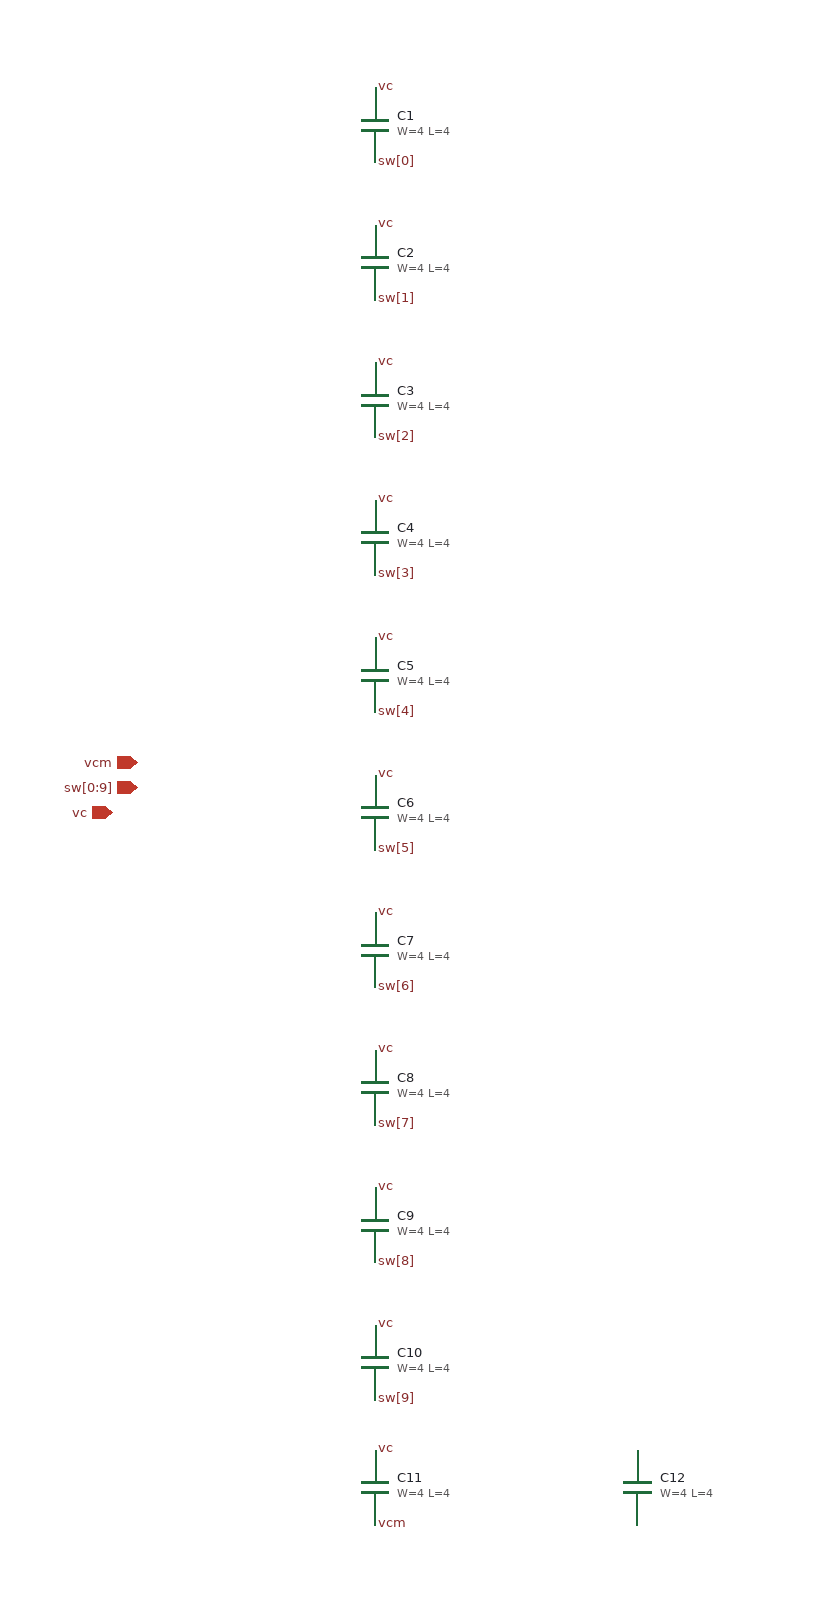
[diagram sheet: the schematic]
v {xschem version=3.4.6 file_version=1.2}
G {}
K {}
V {}
S {}
E {}
C {devices/lab_wire.sym} 420 -90 2 0 {name=p1 sig_type=std_logic lab=vcm}
C {devices/lab_wire.sym} 420 -190 2 0 {name=p3 sig_type=std_logic lab=sw[9]}
C {devices/lab_wire.sym} 420 -300 2 0 {name=p5 sig_type=std_logic lab=sw[8]}
C {devices/lab_wire.sym} 420 -410 2 0 {name=p7 sig_type=std_logic lab=sw[7]}
C {devices/lab_wire.sym} 420 -520 2 0 {name=p9 sig_type=std_logic lab=sw[6]}
C {devices/lab_wire.sym} 420 -630 2 0 {name=p11 sig_type=std_logic lab=sw[5]}
C {devices/lab_wire.sym} 420 -740 2 0 {name=p13 sig_type=std_logic lab=sw[4]}
C {devices/lab_wire.sym} 420 -850 2 0 {name=p15 sig_type=std_logic lab=sw[3]}
C {devices/lab_wire.sym} 420 -960 2 0 {name=p17 sig_type=std_logic lab=sw[2]}
C {devices/ipin.sym} 230 -680 0 0 {name=p53 lab=sw[0:9]}
C {devices/ipin.sym} 230 -700 0 0 {name=p54 lab=vcm}
C {devices/iopin.sym} 210 -660 0 0 {name=p56 lab=vc

}
C {devices/lab_wire.sym} 420 -1020 0 1 {name=p32 sig_type=std_logic lab=vc}
C {sky130_fd_pr/cap_mim_m3_1.sym} 420 -990 0 0 {name=C3 model=cap_mim_m3_1 W=4 L=4 MF=128 spiceprefix=X}
C {devices/lab_wire.sym} 420 -910 0 1 {name=p33 sig_type=std_logic lab=vc}
C {sky130_fd_pr/cap_mim_m3_1.sym} 420 -880 0 0 {name=C4 model=cap_mim_m3_1 W=4 L=4 MF=64 spiceprefix=X}
C {devices/lab_wire.sym} 420 -800 0 1 {name=p34 sig_type=std_logic lab=vc}
C {sky130_fd_pr/cap_mim_m3_1.sym} 420 -770 0 0 {name=C5 model=cap_mim_m3_1 W=4 L=4 MF=32 spiceprefix=X}
C {devices/lab_wire.sym} 420 -690 0 1 {name=p35 sig_type=std_logic lab=vc}
C {sky130_fd_pr/cap_mim_m3_1.sym} 420 -660 0 0 {name=C6 model=cap_mim_m3_1 W=4 L=4 MF=16 spiceprefix=X}
C {devices/lab_wire.sym} 420 -580 0 1 {name=p36 sig_type=std_logic lab=vc}
C {sky130_fd_pr/cap_mim_m3_1.sym} 420 -550 0 0 {name=C7 model=cap_mim_m3_1 W=4 L=4 MF=8 spiceprefix=X}
C {devices/lab_wire.sym} 420 -470 0 1 {name=p37 sig_type=std_logic lab=vc}
C {sky130_fd_pr/cap_mim_m3_1.sym} 420 -440 0 0 {name=C8 model=cap_mim_m3_1 W=4 L=4 MF=4 spiceprefix=X}
C {devices/lab_wire.sym} 420 -360 0 1 {name=p38 sig_type=std_logic lab=vc}
C {sky130_fd_pr/cap_mim_m3_1.sym} 420 -330 0 0 {name=C9 model=cap_mim_m3_1 W=4 L=4 MF=2 spiceprefix=X}
C {devices/lab_wire.sym} 420 -250 0 1 {name=p39 sig_type=std_logic lab=vc}
C {sky130_fd_pr/cap_mim_m3_1.sym} 420 -220 0 0 {name=C10 model=cap_mim_m3_1 W=4 L=4 MF=1 spiceprefix=X}
C {sky130_fd_pr/cap_mim_m3_1.sym} 420 -120 0 0 {name=C11 model=cap_mim_m3_1 W=4 L=4 MF=1 spiceprefix=X}
C {devices/lab_wire.sym} 420 -150 0 1 {name=p71 sig_type=std_logic lab=vc}
C {devices/lab_wire.sym} 420 -1070 2 0 {name=p2 sig_type=std_logic lab=sw[1]}
C {devices/lab_wire.sym} 420 -1180 2 0 {name=p4 sig_type=std_logic lab=sw[0]}
C {devices/lab_wire.sym} 420 -1240 0 1 {name=p6 sig_type=std_logic lab=vc}
C {sky130_fd_pr/cap_mim_m3_1.sym} 420 -1210 0 0 {name=C1 model=cap_mim_m3_1 W=4 L=4 MF=512 spiceprefix=X}
C {devices/lab_wire.sym} 420 -1130 0 1 {name=p8 sig_type=std_logic lab=vc}
C {sky130_fd_pr/cap_mim_m3_1.sym} 420 -1100 0 0 {name=C2 model=cap_mim_m3_1 W=4 L=4 MF=256 spiceprefix=X}
C {sky130_fd_pr/cap_mim_m3_1.sym} 630 -120 0 0 {name=C12 model=cap_mim_m3_1 W=4 L=4 MF=98 spiceprefix=X}
C {devices/noconn.sym} 630 -150 0 0 {name=l1}
C {devices/noconn.sym} 630 -90 0 0 {name=l2}
